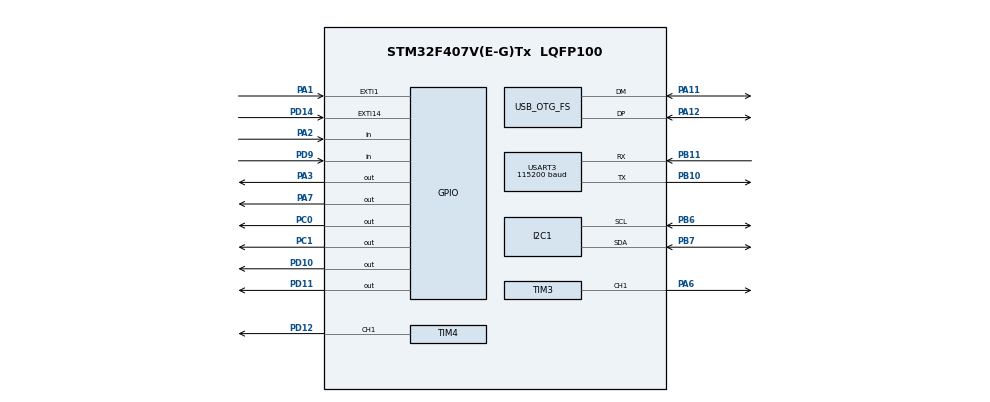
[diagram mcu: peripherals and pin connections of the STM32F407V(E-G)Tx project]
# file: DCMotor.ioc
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Dma.I2C1_RX.0.Direction=DMA_PERIPH_TO_MEMORY
Dma.I2C1_RX.0.FIFOMode=DMA_FIFOMODE_DISABLE
Dma.I2C1_RX.0.Instance=DMA1_Stream0
Dma.I2C1_RX.0.MemDataAlignment=DMA_MDATAALIGN_BYTE
Dma.I2C1_RX.0.MemInc=DMA_MINC_ENABLE
Dma.I2C1_RX.0.Mode=DMA_NORMAL
Dma.I2C1_RX.0.PeriphDataAlignment=DMA_PDATAALIGN_BYTE
Dma.I2C1_RX.0.PeriphInc=DMA_PINC_DISABLE
Dma.I2C1_RX.0.Priority=DMA_PRIORITY_LOW
Dma.Request0=I2C1_RX
I2C1.GeneralCallMode=I2C_GENERALCALL_DISABLE
I2C1.I2C_Mode=I2C_Fast
Mcu.Family=STM32F4
Mcu.Name=STM32F407V(E-G)Tx
Mcu.Package=LQFP100
NVIC.DMA1_Stream0_IRQn=true\:0\:0\:false\:false\:true\:false\:true\:true
NVIC.EXTI15_10_IRQn=true\:0\:0\:false\:false\:true\:true\:true\:true
NVIC.EXTI1_IRQn=true\:0\:0\:false\:false\:true\:true\:true\:true
NVIC.OTG_FS_IRQn=true\:0\:0\:false\:false\:true\:false\:true\:true
NVIC.PriorityGroup=NVIC_PRIORITYGROUP_4
NVIC.TIM1_UP_TIM10_IRQn=true\:15\:0\:false\:false\:true\:false\:true\:true
NVIC.TIM2_IRQn=true\:0\:0\:false\:false\:true\:true\:true\:true
NVIC.TIM8_UP_TIM13_IRQn=true\:0\:0\:false\:false\:true\:true\:true\:true
NVIC.TimeBase=TIM1_UP_TIM10_IRQn
NVIC.TimeBaseIP=TIM1
NVIC.USART3_IRQn=true\:0\:0\:false\:false\:true\:true\:true\:true
PA1.GPIO_PuPd=GPIO_PULLDOWN
PA1.Signal=GPXTI1
PA11.Mode=Device_Only
PA11.Signal=USB_OTG_FS_DM
PA12.Mode=Device_Only
PA12.Signal=USB_OTG_FS_DP
PA13.Mode=Serial_Wire
PA13.Signal=SYS_JTMS-SWDIO
PA14.Mode=Serial_Wire
PA14.Signal=SYS_JTCK-SWCLK
PA2.GPIO_PuPd=GPIO_PULLDOWN
PA2.Signal=GPIO_Input
PA3.Signal=GPIO_Output
PA6.Signal=S_TIM3_CH1
PA7.Signal=GPIO_Output
PB10.Mode=Asynchronous
PB10.Signal=USART3_TX
PB11.Mode=Asynchronous
PB11.Signal=USART3_RX
PB6.Mode=I2C
PB6.Signal=I2C1_SCL
PB7.Mode=I2C
PB7.Signal=I2C1_SDA
PC0.Signal=GPIO_Output
PC1.Signal=GPIO_Output
PD10.Signal=GPIO_Output
PD11.Signal=GPIO_Output
PD12.Signal=S_TIM4_CH1
PD14.GPIO_PuPd=GPIO_PULLDOWN
PD14.Signal=GPXTI14
PD9.GPIO_PuPd=GPIO_PULLDOWN
PD9.Signal=GPIO_Input
PH0-OSC_IN.Mode=HSE-External-Oscillator
PH0-OSC_IN.Signal=RCC_OSC_IN
PH1-OSC_OUT.Mode=HSE-External-Oscillator
PH1-OSC_OUT.Signal=RCC_OSC_OUT
ProjectManager.HeapSize=0x200
ProjectManager.StackSize=0x400
ProjectManager.TargetToolchain=STM32CubeIDE
RCC.48MHZClocksFreq_Value=48000000
RCC.AHBFreq_Value=168000000
RCC.APB1CLKDivider=RCC_HCLK_DIV4
RCC.APB1Freq_Value=42000000
RCC.APB1TimFreq_Value=84000000
RCC.APB2CLKDivider=RCC_HCLK_DIV2
RCC.APB2Freq_Value=84000000
RCC.APB2TimFreq_Value=168000000
RCC.CortexFreq_Value=168000000
RCC.HCLKFreq_Value=168000000
RCC.HSE_VALUE=25000000
RCC.HSI_VALUE=16000000
RCC.LSE_VALUE=32768
RCC.PLLM=25
RCC.PLLN=336
RCC.PLLQ=7
RCC.SYSCLKFreq_VALUE=168000000
RCC.SYSCLKSource=RCC_SYSCLKSOURCE_PLLCLK
RCC.VCOOutputFreq_Value=336000000
SH.S_TIM3_CH1.0=TIM3_CH1,PWM Generation1 CH1
SH.S_TIM4_CH1.0=TIM4_CH1,PWM Generation1 CH1
TIM2.AutoReloadPreload=TIM_AUTORELOAD_PRELOAD_ENABLE
TIM2.Period=149
TIM2.Prescaler=8399
TIM3.Channel-PWM\ Generation1\ CH1=TIM_CHANNEL_1
TIM3.Period=65535
TIM3.Prescaler=0
TIM4.Channel-PWM\ Generation1\ CH1=TIM_CHANNEL_1
TIM8.AutoReloadPreload=TIM_AUTORELOAD_PRELOAD_ENABLE
TIM8.Period=4999
TIM8.Prescaler=167
USART3.BaudRate=115200
USART3.VirtualMode=VM_ASYNC
USB_DEVICE.CLASS_NAME_FS=CDC
USB_DEVICE.VirtualMode-CDC_FS=Cdc
USB_DEVICE.VirtualModeFS=Cdc_FS
USB_OTG_FS.VirtualMode=Device_Only
VP_SYS_VS_tim1.Mode=TIM1
VP_TIM2_VS_ClockSourceINT.Mode=Internal
VP_TIM3_VS_ClockSourceINT.Mode=Internal
VP_TIM4_VS_ClockSourceINT.Mode=Internal
VP_TIM8_VS_ClockSourceINT.Mode=Internal
VP_USB_DEVICE_VS_USB_DEVICE_CDC_FS.Mode=CDC_FS
board=custom

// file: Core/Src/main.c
/* USER CODE BEGIN Header */
/**
  ******************************************************************************
  * @file           : main.c
  * @brief          : Main program body
  ******************************************************************************
  * @attention
  *
  * Copyright (c) 2025 STMicroelectronics.
  * All rights reserved.
  *
  * This software is licensed under terms that can be found in the LICENSE file
  * in the root directory of this software component.
  * If no LICENSE file comes with this software, it is provided AS-IS.
  *
  ******************************************************************************
  */
/* USER CODE END Header */
#include "main.h"
#include "usb_device.h"

/* USER CODE BEGIN Includes */
#include "usbd_cdc_if.h"
#include "stm32f4xx_it.h"
#include <string.h>
/* USER CODE END Includes */

/* USER CODE BEGIN PD */
#define SETPOINT 0.4

/* USER CODE END PD */

I2C_HandleTypeDef hi2c1;
DMA_HandleTypeDef hdma_i2c1_rx;

TIM_HandleTypeDef htim2;
TIM_HandleTypeDef htim3;
TIM_HandleTypeDef htim4;
TIM_HandleTypeDef htim8;

UART_HandleTypeDef huart3;

void SystemClock_Config(void);
static void MX_GPIO_Init(void);
static void MX_DMA_Init(void);
static void MX_TIM3_Init(void);
static void MX_TIM4_Init(void);
static void MX_I2C1_Init(void);
static void MX_USART3_UART_Init(void);
static void MX_TIM2_Init(void);
static void MX_TIM8_Init(void);

/* USER CODE BEGIN 0 */
DCMotor MotorA;
DCMotor MotorB;
MPU6050_Raw Raw;
PID_Param_t PID_speed_A;
PID_Param_t PID_speed_B;
PID_Param_t PID_angle;
float curr_speed = 0;
float sampling_time = 0;
int count = 0;
int count0 = 0;
int prev_dc = 0;

float angle = 0;
float Gyro_angle = 0;
float prev_angle = 0;
float prev_speed = 0;

float total_Az = 0;
float total_Ax = 0;
float total_Gy = 0;
float max_speed = 400;

volatile float Setpoint = SETPOINT;
float max_tilt = MAXTILT;

float Kp_speed = 0.01;
float Ki_speed = 2;
float Kd_speed = 0.00002;

//float Kp_angle = 50;
//float Ki_angle = 0;
//float Kd_angle = 0.1;

float Kp_angle = 16;
float Ki_angle = 350;
float Kd_angle = 0.2;

uint8_t rx_data;
char debug_msg[30];
float pwm_A;
float pwm_B;
float pwm_buffer = 13;
float max_dc;
int8_t move_state = 0;
uint8_t control_lock = LOCKED;
int direction_A;
int direction_B;
void USB_CDC_RxHandler(uint8_t* Buf, uint32_t Len)
{
}

void HAL_GPIO_EXTI_Callback(uint16_t GPIO_Pin) {
	if(GPIO_Pin == ((uint16_t)0x0002)){
		//(uint16_t)0x0002) = GPIO_PIN_1
		if (HAL_GPIO_ReadPin(((GPIO_TypeDef *) GPIOA_BASE), ((uint16_t)0x0004)) == 0) {
			//(uint16_t)0x0004) = GPIO_PIN_2
			MotorA.pulse--;
		}
		else {
			MotorA.pulse++;
		}
	}
	else{
		if (HAL_GPIO_ReadPin(((GPIO_TypeDef *) GPIOD_BASE), ((uint16_t)0x0200)) == 0) {
			//(uint16_t)0x0200) = GPIO_PIN_9
			MotorB.pulse++;
		}
		else {
			MotorB.pulse--;
		}
	}

}
void HAL_UART_RxCpltCallback(UART_HandleTypeDef *huart)
{
  if (huart->Instance == USART3) // Kiểm tra đúng UART nối module
  {
    // Xử lý ký tự nhận được
	sprintf(debug_msg, "Received: %c (ASCII: %d)\r\n", rx_data, rx_data);
	CDC_Transmit_FS((uint8_t*)debug_msg, strlen(debug_msg));
	PID_angle.IntegralSum = 0;
    switch (rx_data) {
      case 'M': // Tiến
    	move_state = FORWARD;
//    	PID_angle.IntegralSum += 10;
        break;
      case 'N': // Lùi
    	move_state = BACKWARD;
        break;
//      case 'O': // Xoay trái
//    	move_state = SPINLEFT;
//        break;
//      case 'P': // Xoay phải
//    	move_state = SPINRIGHT;
//        break;
      case 'B':
    	move_state = TURNRIGHT;
    	break;
      case 'A':
    	move_state = TURNLEFT;
    	break;
      case '0': // Dừng (khi thả tay trên App)
    	move_state = STOP;
    	break;
    }

    // Quan trọng: Phải gọi lại lệnh này để nhận ký tự tiếp theo
    HAL_UART_Receive_IT(&huart3, &rx_data, 1);
  }
}
void CalculateAngle(void){
	MPU6050_Read_Data(&Raw);
	MPU6050_Process_Angle(&Raw);  // Sử dụng hàm đã tối ưu (alpha=0.98, có lọc accelerometer)
	angle = angle_pitch;  // Lấy góc pitch đã được lọc
	DCMotor_CalculateSpeed(&MotorA, CalSpeedTime);
	DCMotor_CalculateSpeed(&MotorB, CalSpeedTime);

	max_dc = 100;
	if(angle >= SETPOINT + 4 || angle <= SETPOINT - 4){
		PID_angle.IntegralSum = 0;
	}

//	sprintf(msg,"sp: %.2f angle: %.2f dc: %d time: %d\r\n",Setpoint, angle,(uint32_t)pwm,HAL_GetTick());

//	sprintf(msg,"angle: %.2f speed A: %.2f speed B: %.2f dc: %d\r\n",angle,MotorA.speed, MotorB.speed,(uint32_t)pwm);
//	sprintf(msg,"speed: %.2f \r\n",MotorA.speed);
//	CDC_Transmit_FS((uint8_t*)msg, strlen(msg));

}
void Balance(void){
//	float desired_speed = -PID_Calculate(&PID_angle, angle);
//	PID_speed_A.Setpoint = desired_speed;
//	PID_speed_B.Setpoint = desired_speed;
//	if(desired_speed < 0) desired_speed = -desired_speed;

	pwm_A = PID_Calculate(&PID_speed_A, MotorA.speed);
	pwm_B = PID_Calculate(&PID_speed_B, MotorB.speed);

	float pwm = -PID_Calculate(&PID_angle, angle);
	pwm_A = pwm;
	pwm_B = pwm;

	  if(pwm_A < 0){
		  pwm_A = -pwm_A;
		  direction_A = BACKWARD;
	  }
	  else{
		  direction_A = FORWARD;
	  }
	  if(pwm_B < 0){
		  pwm_B = -pwm_B;
		  direction_B = BACKWARD;
	  }
	  else{
		  direction_B = FORWARD;
	  }
	  if(pwm_A > 100) pwm_A = 100;
	  if(pwm_B > 100) pwm_B = 100;
	  if(move_state == TURNLEFT) pwm_B = pwm_B*0.5;
	  else if(move_state == TURNRIGHT) pwm_A = pwm_A*0.5;
//	  sprintf(msg,"angle: %.2f IS: %.2f speed:%.2f pwm:%.2f time: %d\r\n", angle,PID_angle.IntegralSum,MotorA.speed,pwm_A,HAL_GetTick());
//	  CDC_Transmit_FS((uint8_t*)msg, strlen(msg));
	  DCMotor_Set_Speed(&MotorB, (uint32_t) pwm_B);
	  DCMotor_Run(&MotorB, direction_B);
	  DCMotor_Set_Speed(&MotorA, (uint32_t) pwm_A);
	  DCMotor_Run(&MotorA, direction_A);
}

/* USER CODE END 0 */

int main(void)
{

  /* USER CODE BEGIN 1 */
	PID_Init(&PID_angle,Kp_angle, Ki_angle, Kd_angle,CalSpeedTime, Setpoint, -25, 25, 1);

	PID_Init(&PID_speed_A, Kp_speed, Ki_speed, Kd_speed, CalSpeedTime, Setpoint, -15, 15, 1);

	PID_Init(&PID_speed_B, Kp_speed, Ki_speed, Kd_speed, CalSpeedTime, Setpoint, -15, 15, 1);

  /* USER CODE END 1 */

  /* MCU Configuration--------------------------------------------------------*/

  /* Reset of all peripherals, Initializes the Flash interface and the Systick. */
  HAL_Init();

  /* Configure the system clock */
  SystemClock_Config();

  /* Initialize all configured peripherals */
  MX_GPIO_Init();
  MX_DMA_Init();
  MX_TIM3_Init();
  MX_TIM4_Init();
  MX_USB_DEVICE_Init();
  MX_I2C1_Init();
  MX_USART3_UART_Init();
  MX_TIM2_Init();
  MX_TIM8_Init();
  /* USER CODE BEGIN 2 */
  MX_USB_DEVICE_Init();
//  HAL_TIM_Base_Start_IT(&htim3);
//  HAL_TIM_Base_Start_IT(&htim4);
  HAL_TIM_PWM_Start(&htim3, TIM_CHANNEL_1);
  HAL_TIM_PWM_Start(&htim4, TIM_CHANNEL_1);
  DCMotor_Init(&MotorA, &htim3, TIM_CHANNEL_1, GPIOA, GPIO_PIN_3, GPIO_PIN_7);
  DCMotor_Init(&MotorB, &htim4, TIM_CHANNEL_1, GPIOD, GPIO_PIN_11, GPIO_PIN_10);
  MPU6050_Init();
  HAL_UART_Receive_IT(&huart3, &rx_data, 1);
  HAL_TIM_Base_Start_IT(&htim2);
  /* USER CODE END 2 */

  /* Infinite loop */
  /* USER CODE BEGIN WHILE */

//  DCMotor_Set_Speed(&MotorA, 100);

 char str[10];
  while (1)
  {
//	  sprintf(str,"H\r\n");
//	  CDC_Transmit_FS((uint8_t*)str, strlen(str));
//	  HAL_Delay(100);
    /* USER CODE END WHILE */

    /* USER CODE BEGIN 3 */

//	  if(control_lock > 0){
//		  control_lock--;
//		  if(control_lock < 0) control_lock = UNLOCKED;
//	  }
//	  else{
//		  control_lock = LOCKED;
//	  }
//	  CalculateAngle();
//	  Balance();
	  if(control_lock == UNLOCKED){
		  control_lock = LOCKED;
		  switch (move_state) {
		  	case STOP:
		  		PID_angle.Ki = Ki_angle;
		  		PID_angle.Kp = Kp_angle;
		  		if(PID_angle.Setpoint > SETPOINT){
		  			PID_angle.Setpoint -= 0.1;
		  			PID_angle.IntegralSum = 0;
		  		}
		  		else if(PID_angle.Setpoint < SETPOINT){
		  			PID_angle.Setpoint += 0.1;
		  			PID_angle.IntegralSum = 0;
		  		}
		  		if(PID_angle.Setpoint < SETPOINT + 0.3 && PID_angle.Setpoint > SETPOINT - 0.3) PID_angle.Setpoint = SETPOINT;
		  		break;
		  	case FORWARD:
	  			PID_angle.IntegralSum = 0;
		    	PID_angle.Ki = 0;
		    	PID_angle.Kp = 12;
		    	PID_angle.Setpoint -= 0.3;
		    	if(PID_angle.Setpoint < SETPOINT-6) PID_angle.Setpoint = SETPOINT-6;
		    	if(MotorA.speed < -800){
		    		PID_angle.Setpoint+=0.4;
		    	}
		    	break;
		    case BACKWARD:
		    	PID_angle.IntegralSum = 0;
		    	PID_angle.Ki = 0;
		    	PID_angle.Kp = 12;
		    	PID_angle.Setpoint += 0.3;
		    	if(PID_angle.Setpoint > 6+SETPOINT) PID_angle.Setpoint = 6 + SETPOINT;
		    	if(MotorA.speed > 800){
		    		PID_angle.Setpoint-=0.4;
		    	}
		    	break;
			case SPINLEFT:
		    	PID_angle.Kp = 12;
				DCMotor_Set_Speed(&MotorA, 35);
				DCMotor_Run(&MotorA, FORWARD);

				break;
			case SPINRIGHT:
		    	PID_angle.Kp = 12;
				DCMotor_Set_Speed(&MotorB, 35);
				DCMotor_Run(&MotorB, FORWARD);
				break;
			case TURNRIGHT:
//				PID_speed_B.Setpoint = MotorA.speed*0.75;
		  		PID_angle.IntegralSum = 0;
		    	PID_angle.Ki = 0;
		    	PID_angle.Kp = 12;
//				pwm_B = PID_Calculate(&PID_speed_B, MotorB.speed);
//				if(pwm_B < 0){
//					pwm_B = -pwm_B;
//					direction_B = BACKWARD;
//				}
//				else{
//					direction_B = FORWARD;
//				}
//	  				if(pwm_B > 100) pwm_B = 100;
//
//				DCMotor_Set_Speed(&MotorB, (uint32_t) pwm_B);
//				DCMotor_Run(&MotorB, direction_B);
				break;
			case TURNLEFT:
//				PID_speed_A.Setpoint = MotorB.speed*0.75;
		  		PID_angle.IntegralSum = 0;
		    	PID_angle.Ki = 0;
		    	PID_angle.Kp = 12;
//				pwm_A = PID_Calculate(&PID_speed_A, MotorA.speed);
//				if(pwm_A < 0){
//					pwm_A = -pwm_A;
//					direction_A = BACKWARD;
//				}
//				else{
//					direction_A = FORWARD;
//				}
//	  			if(pwm_A > 100) pwm_A = 100;
//				DCMotor_Set_Speed(&MotorA, (uint32_t) pwm_A);
//				DCMotor_Run(&MotorA, direction_A);
				break;
			default:
				break;
		}
//		  sprintf(msg,"angle: %.2f sp: %.2f speed:%.2f\r\n", angle,PID_angle.Setpoint,MotorA.speed);
//		  CDC_Transmit_FS(msg, strlen(msg));

	  }

//	  DCMotor_CalculateSpeed(&MotorB, CalSpeedTime);
//	  DCMotor_CalculateSpeed(&MotorA, CalSpeedTime);
//	  float sp = -7000;
//	  PID_speed_A.Setpoint = sp;
//	  PID_speed_B.Setpoint = sp;
//	  if(sp < 0) sp = -sp;
//	  if(sp <= 1000){
//		  PID_speed_A.Ki = 2;
//		  PID_speed_B.Ki = 2;
//	  }
//	  else if(sp <= 5000){
//		  PID_speed_A.Ki = 4;
//		  PID_speed_B.Ki = 4;
//	  }
//	  else{
//		  PID_speed_A.Ki = 6;
//		  PID_speed_B.Ki = 6;
//	  }
//	  pwm_A = PID_Calculate(&PID_speed_A, MotorA.speed);
//	  pwm_B = PID_Calculate(&PID_speed_B, MotorB.speed);
//	  if(pwm_A < 0){
//		  pwm_A = -pwm_A;
//		  direction_A = BACKWARD;
//	  }
//	  else{
//		  direction_A = FORWARD;
//	  }
//	  if(pwm_B < 0){
//		  pwm_B = -pwm_B;
//		  direction_B = BACKWARD;
//	  }
//	  else{
//		  direction_B = FORWARD;
//	  }
//	  if(pwm_A > 100) pwm_A = 100;
//	  if(pwm_B > 100) pwm_B = 100;
//	  DCMotor_Set_Speed(&MotorB, (uint32_t) pwm_B);
////	  DCMotor_Set_Speed(&MotorB, 50);
//	  DCMotor_Run(&MotorB, direction_B);
//	  DCMotor_Set_Speed(&MotorA, (uint32_t) pwm_A);
////	  DCMotor_Set_Speed(&MotorA, 50);
//	  DCMotor_Run(&MotorA, direction_A);
//	  if(count % 4 == 0){
//		  sprintf(msg,"speed A: %.2f speed B: %.2f pwm: %.2f\r\n",MotorA.speed,MotorB.speed,pwm_A);
//		  CDC_Transmit_FS(msg, strlen(msg));
//	  }
//	  count = count+1;
//
//	  HAL_Delay(5);
  }
  /* USER CODE END 3 */
}

void SystemClock_Config(void)
{
  RCC_OscInitTypeDef RCC_OscInitStruct = {0};
  RCC_ClkInitTypeDef RCC_ClkInitStruct = {0};

  /** Configure the main internal regulator output voltage
  */
  __HAL_RCC_PWR_CLK_ENABLE();
  __HAL_PWR_VOLTAGESCALING_CONFIG(PWR_REGULATOR_VOLTAGE_SCALE1);

  /** Initializes the RCC Oscillators according to the specified parameters
  * in the RCC_OscInitTypeDef structure.
  */
  RCC_OscInitStruct.OscillatorType = RCC_OSCILLATORTYPE_HSE;
  RCC_OscInitStruct.HSEState = RCC_HSE_ON;
  RCC_OscInitStruct.PLL.PLLState = RCC_PLL_ON;
  RCC_OscInitStruct.PLL.PLLSource = RCC_PLLSOURCE_HSE;
  RCC_OscInitStruct.PLL.PLLM = 8;
  RCC_OscInitStruct.PLL.PLLN = 336;
  RCC_OscInitStruct.PLL.PLLP = RCC_PLLP_DIV2;
  RCC_OscInitStruct.PLL.PLLQ = 7;
  if (HAL_RCC_OscConfig(&RCC_OscInitStruct) != HAL_OK)
  {
    Error_Handler();
  }

  /** Initializes the CPU, AHB and APB buses clocks
  */
  RCC_ClkInitStruct.ClockType = RCC_CLOCKTYPE_HCLK|RCC_CLOCKTYPE_SYSCLK
                              |RCC_CLOCKTYPE_PCLK1|RCC_CLOCKTYPE_PCLK2;
  RCC_ClkInitStruct.SYSCLKSource = RCC_SYSCLKSOURCE_PLLCLK;
  RCC_ClkInitStruct.AHBCLKDivider = RCC_SYSCLK_DIV1;
  RCC_ClkInitStruct.APB1CLKDivider = RCC_HCLK_DIV4;
  RCC_ClkInitStruct.APB2CLKDivider = RCC_HCLK_DIV2;

  if (HAL_RCC_ClockConfig(&RCC_ClkInitStruct, FLASH_LATENCY_5) != HAL_OK)
  {
    Error_Handler();
  }
}

static void MX_I2C1_Init(void)
{

  hi2c1.Instance = I2C1;
  hi2c1.Init.ClockSpeed = 400000;
  hi2c1.Init.DutyCycle = I2C_DUTYCYCLE_2;
  hi2c1.Init.OwnAddress1 = 0;
  hi2c1.Init.AddressingMode = I2C_ADDRESSINGMODE_7BIT;
  hi2c1.Init.DualAddressMode = I2C_DUALADDRESS_DISABLE;
  hi2c1.Init.OwnAddress2 = 0;
  hi2c1.Init.GeneralCallMode = I2C_GENERALCALL_DISABLE;
  hi2c1.Init.NoStretchMode = I2C_NOSTRETCH_DISABLE;
  if (HAL_I2C_Init(&hi2c1) != HAL_OK)
  {
    Error_Handler();
  }

}

static void MX_TIM2_Init(void)
{

  TIM_ClockConfigTypeDef sClockSourceConfig = {0};
  TIM_MasterConfigTypeDef sMasterConfig = {0};

  htim2.Instance = TIM2;
  htim2.Init.Prescaler = 8399;
  htim2.Init.CounterMode = TIM_COUNTERMODE_UP;
  htim2.Init.Period = 149;
  htim2.Init.ClockDivision = TIM_CLOCKDIVISION_DIV1;
  htim2.Init.AutoReloadPreload = TIM_AUTORELOAD_PRELOAD_ENABLE;
  if (HAL_TIM_Base_Init(&htim2) != HAL_OK)
  {
    Error_Handler();
  }
  sClockSourceConfig.ClockSource = TIM_CLOCKSOURCE_INTERNAL;
  if (HAL_TIM_ConfigClockSource(&htim2, &sClockSourceConfig) != HAL_OK)
  {
    Error_Handler();
  }
  sMasterConfig.MasterOutputTrigger = TIM_TRGO_RESET;
  sMasterConfig.MasterSlaveMode = TIM_MASTERSLAVEMODE_DISABLE;
  if (HAL_TIMEx_MasterConfigSynchronization(&htim2, &sMasterConfig) != HAL_OK)
  {
    Error_Handler();
  }

}

static void MX_TIM3_Init(void)
{

  TIM_ClockConfigTypeDef sClockSourceConfig = {0};
  TIM_MasterConfigTypeDef sMasterConfig = {0};
  TIM_OC_InitTypeDef sConfigOC = {0};

  htim3.Instance = TIM3;
  htim3.Init.Prescaler = 0;
  htim3.Init.CounterMode = TIM_COUNTERMODE_UP;
  htim3.Init.Period = 65535;
  htim3.Init.ClockDivision = TIM_CLOCKDIVISION_DIV1;
  htim3.Init.AutoReloadPreload = TIM_AUTORELOAD_PRELOAD_DISABLE;
  if (HAL_TIM_Base_Init(&htim3) != HAL_OK)
  {
    Error_Handler();
  }
  sClockSourceConfig.ClockSource = TIM_CLOCKSOURCE_INTERNAL;
  if (HAL_TIM_ConfigClockSource(&htim3, &sClockSourceConfig) != HAL_OK)
  {
    Error_Handler();
  }
  if (HAL_TIM_PWM_Init(&htim3) != HAL_OK)
  {
    Error_Handler();
  }
  sMasterConfig.MasterOutputTrigger = TIM_TRGO_RESET;
  sMasterConfig.MasterSlaveMode = TIM_MASTERSLAVEMODE_DISABLE;
  if (HAL_TIMEx_MasterConfigSynchronization(&htim3, &sMasterConfig) != HAL_OK)
  {
    Error_Handler();
  }
  sConfigOC.OCMode = TIM_OCMODE_PWM1;
  sConfigOC.Pulse = 0;
  sConfigOC.OCPolarity = TIM_OCPOLARITY_HIGH;
  sConfigOC.OCFastMode = TIM_OCFAST_DISABLE;
  if (HAL_TIM_PWM_ConfigChannel(&htim3, &sConfigOC, TIM_CHANNEL_1) != HAL_OK)
  {
    Error_Handler();
  }
  HAL_TIM_MspPostInit(&htim3);

}

static void MX_TIM4_Init(void)
{

  TIM_ClockConfigTypeDef sClockSourceConfig = {0};
  TIM_MasterConfigTypeDef sMasterConfig = {0};
  TIM_OC_InitTypeDef sConfigOC = {0};

  htim4.Instance = TIM4;
  htim4.Init.Prescaler = 0;
  htim4.Init.CounterMode = TIM_COUNTERMODE_UP;
  htim4.Init.Period = 65535;
  htim4.Init.ClockDivision = TIM_CLOCKDIVISION_DIV1;
  htim4.Init.AutoReloadPreload = TIM_AUTORELOAD_PRELOAD_DISABLE;
  if (HAL_TIM_Base_Init(&htim4) != HAL_OK)
  {
    Error_Handler();
  }
  sClockSourceConfig.ClockSource = TIM_CLOCKSOURCE_INTERNAL;
  if (HAL_TIM_ConfigClockSource(&htim4, &sClockSourceConfig) != HAL_OK)
  {
    Error_Handler();
  }
  if (HAL_TIM_PWM_Init(&htim4) != HAL_OK)
  {
    Error_Handler();
  }
  sMasterConfig.MasterOutputTrigger = TIM_TRGO_RESET;
  sMasterConfig.MasterSlaveMode = TIM_MASTERSLAVEMODE_DISABLE;
  if (HAL_TIMEx_MasterConfigSynchronization(&htim4, &sMasterConfig) != HAL_OK)
  {
    Error_Handler();
  }
  sConfigOC.OCMode = TIM_OCMODE_PWM1;
  sConfigOC.Pulse = 0;
  sConfigOC.OCPolarity = TIM_OCPOLARITY_HIGH;
  sConfigOC.OCFastMode = TIM_OCFAST_DISABLE;
  if (HAL_TIM_PWM_ConfigChannel(&htim4, &sConfigOC, TIM_CHANNEL_1) != HAL_OK)
  {
    Error_Handler();
  }
  HAL_TIM_MspPostInit(&htim4);

}

static void MX_TIM8_Init(void)
{

  TIM_ClockConfigTypeDef sClockSourceConfig = {0};
  TIM_MasterConfigTypeDef sMasterConfig = {0};

  htim8.Instance = TIM8;
  htim8.Init.Prescaler = 167;
  htim8.Init.CounterMode = TIM_COUNTERMODE_UP;
  htim8.Init.Period = 9999;
  htim8.Init.ClockDivision = TIM_CLOCKDIVISION_DIV1;
  htim8.Init.RepetitionCounter = 0;
  htim8.Init.AutoReloadPreload = TIM_AUTORELOAD_PRELOAD_ENABLE;
  if (HAL_TIM_Base_Init(&htim8) != HAL_OK)
  {
    Error_Handler();
  }
  sClockSourceConfig.ClockSource = TIM_CLOCKSOURCE_INTERNAL;
  if (HAL_TIM_ConfigClockSource(&htim8, &sClockSourceConfig) != HAL_OK)
  {
    Error_Handler();
  }
  sMasterConfig.MasterOutputTrigger = TIM_TRGO_RESET;
  sMasterConfig.MasterSlaveMode = TIM_MASTERSLAVEMODE_DISABLE;
  if (HAL_TIMEx_MasterConfigSynchronization(&htim8, &sMasterConfig) != HAL_OK)
  {
    Error_Handler();
  }

}

static void MX_USART3_UART_Init(void)
{

  huart3.Instance = USART3;
  huart3.Init.BaudRate = 115200;
  huart3.Init.WordLength = UART_WORDLENGTH_8B;
  huart3.Init.StopBits = UART_STOPBITS_1;
  huart3.Init.Parity = UART_PARITY_NONE;
  huart3.Init.Mode = UART_MODE_TX_RX;
  huart3.Init.HwFlowCtl = UART_HWCONTROL_NONE;
  huart3.Init.OverSampling = UART_OVERSAMPLING_16;
  if (HAL_UART_Init(&huart3) != HAL_OK)
  {
    Error_Handler();
  }

}

static void MX_DMA_Init(void)
{

  /* DMA controller clock enable */
  __HAL_RCC_DMA1_CLK_ENABLE();

  /* DMA interrupt init */
  /* DMA1_Stream0_IRQn interrupt configuration */
  HAL_NVIC_SetPriority(DMA1_Stream0_IRQn, 0, 0);
  HAL_NVIC_EnableIRQ(DMA1_Stream0_IRQn);

}

static void MX_GPIO_Init(void)
{
  GPIO_InitTypeDef GPIO_InitStruct = {0};

  /* GPIO Ports Clock Enable */
  __HAL_RCC_GPIOH_CLK_ENABLE();
  __HAL_RCC_GPIOC_CLK_ENABLE();
  __HAL_RCC_GPIOA_CLK_ENABLE();
  __HAL_RCC_GPIOB_CLK_ENABLE();
  __HAL_RCC_GPIOD_CLK_ENABLE();

  /*Configure GPIO pin Output Level */
  HAL_GPIO_WritePin(GPIOC, GPIO_PIN_0|GPIO_PIN_1, GPIO_PIN_RESET);

  /*Configure GPIO pin Output Level */
  HAL_GPIO_WritePin(GPIOA, GPIO_PIN_3|GPIO_PIN_7, GPIO_PIN_RESET);

  /*Configure GPIO pin Output Level */
  HAL_GPIO_WritePin(GPIOD, GPIO_PIN_10|GPIO_PIN_11, GPIO_PIN_RESET);

  /*Configure GPIO pins : PC0 PC1 */
  GPIO_InitStruct.Pin = GPIO_PIN_0|GPIO_PIN_1;
  GPIO_InitStruct.Mode = GPIO_MODE_OUTPUT_PP;
  GPIO_InitStruct.Pull = GPIO_NOPULL;
  GPIO_InitStruct.Speed = GPIO_SPEED_FREQ_LOW;
  HAL_GPIO_Init(GPIOC, &GPIO_InitStruct);

  /*Configure GPIO pin : PA1 */
  GPIO_InitStruct.Pin = GPIO_PIN_1;
  GPIO_InitStruct.Mode = GPIO_MODE_IT_RISING;
  GPIO_InitStruct.Pull = GPIO_PULLDOWN;
  HAL_GPIO_Init(GPIOA, &GPIO_InitStruct);

  /*Configure GPIO pin : PA2 */
  GPIO_InitStruct.Pin = GPIO_PIN_2;
  GPIO_InitStruct.Mode = GPIO_MODE_INPUT;
  GPIO_InitStruct.Pull = GPIO_PULLDOWN;
  HAL_GPIO_Init(GPIOA, &GPIO_InitStruct);

  /*Configure GPIO pins : PA3 PA7 */
  GPIO_InitStruct.Pin = GPIO_PIN_3|GPIO_PIN_7;
  GPIO_InitStruct.Mode = GPIO_MODE_OUTPUT_PP;
  GPIO_InitStruct.Pull = GPIO_NOPULL;
  GPIO_InitStruct.Speed = GPIO_SPEED_FREQ_LOW;
  HAL_GPIO_Init(GPIOA, &GPIO_InitStruct);

  /*Configure GPIO pin : PD9 */
  GPIO_InitStruct.Pin = GPIO_PIN_9;
  GPIO_InitStruct.Mode = GPIO_MODE_INPUT;
  GPIO_InitStruct.Pull = GPIO_PULLDOWN;
  HAL_GPIO_Init(GPIOD, &GPIO_InitStruct);

  /*Configure GPIO pins : PD10 PD11 */
  GPIO_InitStruct.Pin = GPIO_PIN_10|GPIO_PIN_11;
  GPIO_InitStruct.Mode = GPIO_MODE_OUTPUT_PP;
  GPIO_InitStruct.Pull = GPIO_NOPULL;
  GPIO_InitStruct.Speed = GPIO_SPEED_FREQ_LOW;
  HAL_GPIO_Init(GPIOD, &GPIO_InitStruct);

  /*Configure GPIO pin : PD14 */
  GPIO_InitStruct.Pin = GPIO_PIN_14;
  GPIO_InitStruct.Mode = GPIO_MODE_IT_RISING;
  GPIO_InitStruct.Pull = GPIO_PULLDOWN;
  HAL_GPIO_Init(GPIOD, &GPIO_InitStruct);

  /* EXTI interrupt init*/
  HAL_NVIC_SetPriority(EXTI1_IRQn, 0, 0);
  HAL_NVIC_EnableIRQ(EXTI1_IRQn);

  HAL_NVIC_SetPriority(EXTI15_10_IRQn, 0, 0);
  HAL_NVIC_EnableIRQ(EXTI15_10_IRQn);

}

void HAL_TIM_PeriodElapsedCallback(TIM_HandleTypeDef *htim)
{
  if (htim->Instance == TIM1)
  {
    HAL_IncTick();
  }
  /* USER CODE BEGIN Callback 1 */
  if(htim->Instance == TIM2){
	  if(control_lock > 0){
		  control_lock--;
		  if(control_lock < 0) control_lock = UNLOCKED;
	  }
	  else{
		  control_lock = LOCKED;
	  }
	  CalculateAngle();
	  Balance();
	  sprintf(msg,"speed A: %.2f angle: %.2f pwm: %.2f time: %d\r\n",MotorA.speed,angle,pwm_A,HAL_GetTick());
	  CDC_Transmit_FS(msg, strlen(msg));
  }

  /* USER CODE END Callback 1 */
}

void Error_Handler(void)
{
  __disable_irq();
  while (1)
  {
  }
}
